VERSION 5.7 ;
  NOWIREEXTENSIONATPIN ON ;
  DIVIDERCHAR "/" ;
  BUSBITCHARS "[]" ;
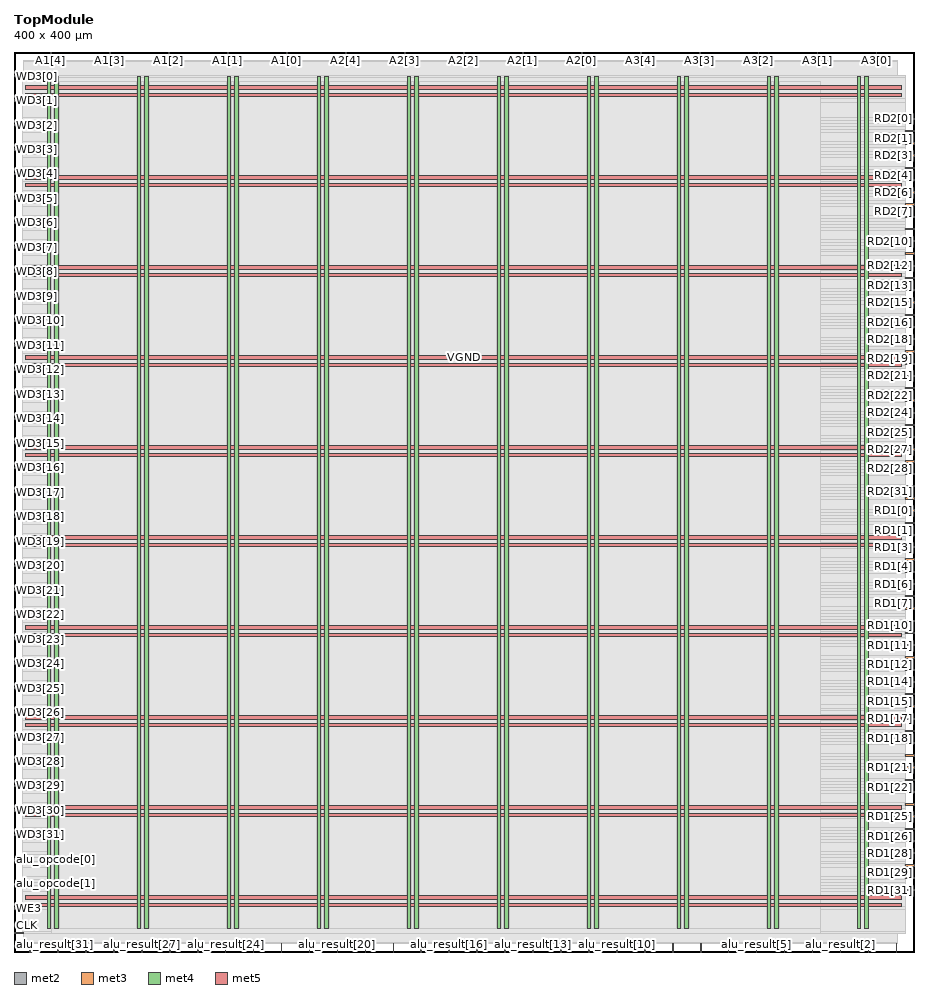
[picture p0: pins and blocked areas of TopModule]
MACRO TopModule
  CLASS BLOCK ;
  FOREIGN TopModule ;
  ORIGIN 0.000 0.000 ;
  SIZE 400.000 BY 400.000 ;
  PIN A1[0]
    DIRECTION INPUT ;
    USE SIGNAL ;
    ANTENNAGATEAREA 0.213000 ;
    PORT
      LAYER met2 ;
        RECT 121.070 396.000 121.350 400.000 ;
    END
  END A1[0]
  PIN A1[1]
    DIRECTION INPUT ;
    USE SIGNAL ;
    ANTENNAGATEAREA 0.159000 ;
    PORT
      LAYER met2 ;
        RECT 94.850 396.000 95.130 400.000 ;
    END
  END A1[1]
  PIN A1[2]
    DIRECTION INPUT ;
    USE SIGNAL ;
    ANTENNAGATEAREA 0.126000 ;
    PORT
      LAYER met2 ;
        RECT 68.630 396.000 68.910 400.000 ;
    END
  END A1[2]
  PIN A1[3]
    DIRECTION INPUT ;
    USE SIGNAL ;
    ANTENNAGATEAREA 0.159000 ;
    PORT
      LAYER met2 ;
        RECT 42.410 396.000 42.690 400.000 ;
    END
  END A1[3]
  PIN A1[4]
    DIRECTION INPUT ;
    USE SIGNAL ;
    ANTENNAGATEAREA 0.247500 ;
    PORT
      LAYER met2 ;
        RECT 16.190 396.000 16.470 400.000 ;
    END
  END A1[4]
  PIN A2[0]
    DIRECTION INPUT ;
    USE SIGNAL ;
    ANTENNAGATEAREA 0.990000 ;
    PORT
      LAYER met2 ;
        RECT 252.170 396.000 252.450 400.000 ;
    END
  END A2[0]
  PIN A2[1]
    DIRECTION INPUT ;
    USE SIGNAL ;
    ANTENNAGATEAREA 0.852000 ;
    PORT
      LAYER met2 ;
        RECT 225.950 396.000 226.230 400.000 ;
    END
  END A2[1]
  PIN A2[2]
    DIRECTION INPUT ;
    USE SIGNAL ;
    ANTENNAGATEAREA 0.159000 ;
    PORT
      LAYER met2 ;
        RECT 199.730 396.000 200.010 400.000 ;
    END
  END A2[2]
  PIN A2[3]
    DIRECTION INPUT ;
    USE SIGNAL ;
    ANTENNAGATEAREA 0.196500 ;
    PORT
      LAYER met2 ;
        RECT 173.510 396.000 173.790 400.000 ;
    END
  END A2[3]
  PIN A2[4]
    DIRECTION INPUT ;
    USE SIGNAL ;
    ANTENNAGATEAREA 0.213000 ;
    PORT
      LAYER met2 ;
        RECT 147.290 396.000 147.570 400.000 ;
    END
  END A2[4]
  PIN A3[0]
    DIRECTION INPUT ;
    USE SIGNAL ;
    ANTENNAGATEAREA 0.213000 ;
    PORT
      LAYER met2 ;
        RECT 383.270 396.000 383.550 400.000 ;
    END
  END A3[0]
  PIN A3[1]
    DIRECTION INPUT ;
    USE SIGNAL ;
    ANTENNAGATEAREA 0.247500 ;
    PORT
      LAYER met2 ;
        RECT 357.050 396.000 357.330 400.000 ;
    END
  END A3[1]
  PIN A3[2]
    DIRECTION INPUT ;
    USE SIGNAL ;
    ANTENNAGATEAREA 0.213000 ;
    PORT
      LAYER met2 ;
        RECT 330.830 396.000 331.110 400.000 ;
    END
  END A3[2]
  PIN A3[3]
    DIRECTION INPUT ;
    USE SIGNAL ;
    ANTENNAGATEAREA 0.213000 ;
    PORT
      LAYER met2 ;
        RECT 304.610 396.000 304.890 400.000 ;
    END
  END A3[3]
  PIN A3[4]
    DIRECTION INPUT ;
    USE SIGNAL ;
    ANTENNAGATEAREA 0.159000 ;
    PORT
      LAYER met2 ;
        RECT 278.390 396.000 278.670 400.000 ;
    END
  END A3[4]
  PIN CLK
    DIRECTION INPUT ;
    USE SIGNAL ;
    ANTENNAGATEAREA 0.852000 ;
    ANTENNADIFFAREA 0.434700 ;
    PORT
      LAYER met3 ;
        RECT 0.000 8.200 4.000 8.800 ;
    END
  END CLK
  PIN RD1[0]
    DIRECTION OUTPUT ;
    USE SIGNAL ;
    ANTENNADIFFAREA 0.340600 ;
    PORT
      LAYER met3 ;
        RECT 396.000 195.880 400.000 196.480 ;
    END
  END RD1[0]
  PIN RD1[10]
    DIRECTION OUTPUT ;
    USE SIGNAL ;
    ANTENNADIFFAREA 0.340600 ;
    PORT
      LAYER met3 ;
        RECT 396.000 141.480 400.000 142.080 ;
    END
  END RD1[10]
  PIN RD1[11]
    DIRECTION OUTPUT ;
    USE SIGNAL ;
    ANTENNADIFFAREA 0.340600 ;
    PORT
      LAYER met3 ;
        RECT 396.000 136.040 400.000 136.640 ;
    END
  END RD1[11]
  PIN RD1[12]
    DIRECTION OUTPUT ;
    USE SIGNAL ;
    ANTENNADIFFAREA 0.340600 ;
    PORT
      LAYER met3 ;
        RECT 396.000 130.600 400.000 131.200 ;
    END
  END RD1[12]
  PIN RD1[13]
    DIRECTION OUTPUT ;
    USE SIGNAL ;
    ANTENNADIFFAREA 0.340600 ;
    PORT
      LAYER met3 ;
        RECT 396.000 125.160 400.000 125.760 ;
    END
  END RD1[13]
  PIN RD1[14]
    DIRECTION OUTPUT ;
    USE SIGNAL ;
    ANTENNADIFFAREA 0.340600 ;
    PORT
      LAYER met3 ;
        RECT 396.000 119.720 400.000 120.320 ;
    END
  END RD1[14]
  PIN RD1[15]
    DIRECTION OUTPUT ;
    USE SIGNAL ;
    ANTENNADIFFAREA 0.340600 ;
    PORT
      LAYER met3 ;
        RECT 396.000 114.280 400.000 114.880 ;
    END
  END RD1[15]
  PIN RD1[16]
    DIRECTION OUTPUT ;
    USE SIGNAL ;
    ANTENNADIFFAREA 0.340600 ;
    PORT
      LAYER met3 ;
        RECT 396.000 108.840 400.000 109.440 ;
    END
  END RD1[16]
  PIN RD1[17]
    DIRECTION OUTPUT ;
    USE SIGNAL ;
    ANTENNADIFFAREA 0.340600 ;
    PORT
      LAYER met3 ;
        RECT 396.000 103.400 400.000 104.000 ;
    END
  END RD1[17]
  PIN RD1[18]
    DIRECTION OUTPUT ;
    USE SIGNAL ;
    ANTENNADIFFAREA 0.340600 ;
    PORT
      LAYER met3 ;
        RECT 396.000 97.960 400.000 98.560 ;
    END
  END RD1[18]
  PIN RD1[19]
    DIRECTION OUTPUT ;
    USE SIGNAL ;
    ANTENNADIFFAREA 0.340600 ;
    PORT
      LAYER met3 ;
        RECT 396.000 92.520 400.000 93.120 ;
    END
  END RD1[19]
  PIN RD1[1]
    DIRECTION OUTPUT ;
    USE SIGNAL ;
    ANTENNADIFFAREA 0.340600 ;
    PORT
      LAYER met3 ;
        RECT 396.000 190.440 400.000 191.040 ;
    END
  END RD1[1]
  PIN RD1[20]
    DIRECTION OUTPUT ;
    USE SIGNAL ;
    ANTENNADIFFAREA 0.340600 ;
    PORT
      LAYER met3 ;
        RECT 396.000 87.080 400.000 87.680 ;
    END
  END RD1[20]
  PIN RD1[21]
    DIRECTION OUTPUT ;
    USE SIGNAL ;
    ANTENNADIFFAREA 0.340600 ;
    PORT
      LAYER met3 ;
        RECT 396.000 81.640 400.000 82.240 ;
    END
  END RD1[21]
  PIN RD1[22]
    DIRECTION OUTPUT ;
    USE SIGNAL ;
    ANTENNADIFFAREA 0.340600 ;
    PORT
      LAYER met3 ;
        RECT 396.000 76.200 400.000 76.800 ;
    END
  END RD1[22]
  PIN RD1[23]
    DIRECTION OUTPUT ;
    USE SIGNAL ;
    ANTENNADIFFAREA 0.340600 ;
    PORT
      LAYER met3 ;
        RECT 396.000 70.760 400.000 71.360 ;
    END
  END RD1[23]
  PIN RD1[24]
    DIRECTION OUTPUT ;
    USE SIGNAL ;
    ANTENNADIFFAREA 0.340600 ;
    PORT
      LAYER met3 ;
        RECT 396.000 65.320 400.000 65.920 ;
    END
  END RD1[24]
  PIN RD1[25]
    DIRECTION OUTPUT ;
    USE SIGNAL ;
    ANTENNADIFFAREA 0.340600 ;
    PORT
      LAYER met3 ;
        RECT 396.000 59.880 400.000 60.480 ;
    END
  END RD1[25]
  PIN RD1[26]
    DIRECTION OUTPUT ;
    USE SIGNAL ;
    ANTENNADIFFAREA 0.340600 ;
    PORT
      LAYER met3 ;
        RECT 396.000 54.440 400.000 55.040 ;
    END
  END RD1[26]
  PIN RD1[27]
    DIRECTION OUTPUT ;
    USE SIGNAL ;
    ANTENNADIFFAREA 0.340600 ;
    PORT
      LAYER met3 ;
        RECT 396.000 49.000 400.000 49.600 ;
    END
  END RD1[27]
  PIN RD1[28]
    DIRECTION OUTPUT ;
    USE SIGNAL ;
    ANTENNADIFFAREA 0.340600 ;
    PORT
      LAYER met3 ;
        RECT 396.000 43.560 400.000 44.160 ;
    END
  END RD1[28]
  PIN RD1[29]
    DIRECTION OUTPUT ;
    USE SIGNAL ;
    ANTENNADIFFAREA 0.340600 ;
    PORT
      LAYER met3 ;
        RECT 396.000 38.120 400.000 38.720 ;
    END
  END RD1[29]
  PIN RD1[2]
    DIRECTION OUTPUT ;
    USE SIGNAL ;
    ANTENNADIFFAREA 0.340600 ;
    PORT
      LAYER met3 ;
        RECT 396.000 185.000 400.000 185.600 ;
    END
  END RD1[2]
  PIN RD1[30]
    DIRECTION OUTPUT ;
    USE SIGNAL ;
    ANTENNADIFFAREA 0.340600 ;
    PORT
      LAYER met3 ;
        RECT 396.000 32.680 400.000 33.280 ;
    END
  END RD1[30]
  PIN RD1[31]
    DIRECTION OUTPUT ;
    USE SIGNAL ;
    ANTENNADIFFAREA 0.340600 ;
    PORT
      LAYER met3 ;
        RECT 396.000 27.240 400.000 27.840 ;
    END
  END RD1[31]
  PIN RD1[3]
    DIRECTION OUTPUT ;
    USE SIGNAL ;
    ANTENNADIFFAREA 0.340600 ;
    PORT
      LAYER met3 ;
        RECT 396.000 179.560 400.000 180.160 ;
    END
  END RD1[3]
  PIN RD1[4]
    DIRECTION OUTPUT ;
    USE SIGNAL ;
    ANTENNADIFFAREA 0.340600 ;
    PORT
      LAYER met3 ;
        RECT 396.000 174.120 400.000 174.720 ;
    END
  END RD1[4]
  PIN RD1[5]
    DIRECTION OUTPUT ;
    USE SIGNAL ;
    ANTENNADIFFAREA 0.340600 ;
    PORT
      LAYER met3 ;
        RECT 396.000 168.680 400.000 169.280 ;
    END
  END RD1[5]
  PIN RD1[6]
    DIRECTION OUTPUT ;
    USE SIGNAL ;
    ANTENNADIFFAREA 0.340600 ;
    PORT
      LAYER met3 ;
        RECT 396.000 163.240 400.000 163.840 ;
    END
  END RD1[6]
  PIN RD1[7]
    DIRECTION OUTPUT ;
    USE SIGNAL ;
    ANTENNADIFFAREA 0.340600 ;
    PORT
      LAYER met3 ;
        RECT 396.000 157.800 400.000 158.400 ;
    END
  END RD1[7]
  PIN RD1[8]
    DIRECTION OUTPUT ;
    USE SIGNAL ;
    ANTENNADIFFAREA 0.340600 ;
    PORT
      LAYER met3 ;
        RECT 396.000 152.360 400.000 152.960 ;
    END
  END RD1[8]
  PIN RD1[9]
    DIRECTION OUTPUT ;
    USE SIGNAL ;
    ANTENNADIFFAREA 0.340600 ;
    PORT
      LAYER met3 ;
        RECT 396.000 146.920 400.000 147.520 ;
    END
  END RD1[9]
  PIN RD2[0]
    DIRECTION OUTPUT ;
    USE SIGNAL ;
    ANTENNADIFFAREA 0.340600 ;
    PORT
      LAYER met3 ;
        RECT 396.000 369.960 400.000 370.560 ;
    END
  END RD2[0]
  PIN RD2[10]
    DIRECTION OUTPUT ;
    USE SIGNAL ;
    ANTENNADIFFAREA 0.340600 ;
    PORT
      LAYER met3 ;
        RECT 396.000 315.560 400.000 316.160 ;
    END
  END RD2[10]
  PIN RD2[11]
    DIRECTION OUTPUT ;
    USE SIGNAL ;
    ANTENNADIFFAREA 0.340600 ;
    PORT
      LAYER met3 ;
        RECT 396.000 310.120 400.000 310.720 ;
    END
  END RD2[11]
  PIN RD2[12]
    DIRECTION OUTPUT ;
    USE SIGNAL ;
    ANTENNADIFFAREA 0.340600 ;
    PORT
      LAYER met3 ;
        RECT 396.000 304.680 400.000 305.280 ;
    END
  END RD2[12]
  PIN RD2[13]
    DIRECTION OUTPUT ;
    USE SIGNAL ;
    ANTENNADIFFAREA 0.340600 ;
    PORT
      LAYER met3 ;
        RECT 396.000 299.240 400.000 299.840 ;
    END
  END RD2[13]
  PIN RD2[14]
    DIRECTION OUTPUT ;
    USE SIGNAL ;
    ANTENNADIFFAREA 0.340600 ;
    PORT
      LAYER met3 ;
        RECT 396.000 293.800 400.000 294.400 ;
    END
  END RD2[14]
  PIN RD2[15]
    DIRECTION OUTPUT ;
    USE SIGNAL ;
    ANTENNADIFFAREA 0.340600 ;
    PORT
      LAYER met3 ;
        RECT 396.000 288.360 400.000 288.960 ;
    END
  END RD2[15]
  PIN RD2[16]
    DIRECTION OUTPUT ;
    USE SIGNAL ;
    ANTENNADIFFAREA 0.340600 ;
    PORT
      LAYER met3 ;
        RECT 396.000 282.920 400.000 283.520 ;
    END
  END RD2[16]
  PIN RD2[17]
    DIRECTION OUTPUT ;
    USE SIGNAL ;
    ANTENNADIFFAREA 0.340600 ;
    PORT
      LAYER met3 ;
        RECT 396.000 277.480 400.000 278.080 ;
    END
  END RD2[17]
  PIN RD2[18]
    DIRECTION OUTPUT ;
    USE SIGNAL ;
    ANTENNADIFFAREA 0.340600 ;
    PORT
      LAYER met3 ;
        RECT 396.000 272.040 400.000 272.640 ;
    END
  END RD2[18]
  PIN RD2[19]
    DIRECTION OUTPUT ;
    USE SIGNAL ;
    ANTENNADIFFAREA 0.340600 ;
    PORT
      LAYER met3 ;
        RECT 396.000 266.600 400.000 267.200 ;
    END
  END RD2[19]
  PIN RD2[1]
    DIRECTION OUTPUT ;
    USE SIGNAL ;
    ANTENNADIFFAREA 0.340600 ;
    PORT
      LAYER met3 ;
        RECT 396.000 364.520 400.000 365.120 ;
    END
  END RD2[1]
  PIN RD2[20]
    DIRECTION OUTPUT ;
    USE SIGNAL ;
    ANTENNADIFFAREA 0.340600 ;
    PORT
      LAYER met3 ;
        RECT 396.000 261.160 400.000 261.760 ;
    END
  END RD2[20]
  PIN RD2[21]
    DIRECTION OUTPUT ;
    USE SIGNAL ;
    ANTENNADIFFAREA 0.340600 ;
    PORT
      LAYER met3 ;
        RECT 396.000 255.720 400.000 256.320 ;
    END
  END RD2[21]
  PIN RD2[22]
    DIRECTION OUTPUT ;
    USE SIGNAL ;
    ANTENNADIFFAREA 0.340600 ;
    PORT
      LAYER met3 ;
        RECT 396.000 250.280 400.000 250.880 ;
    END
  END RD2[22]
  PIN RD2[23]
    DIRECTION OUTPUT ;
    USE SIGNAL ;
    ANTENNADIFFAREA 0.340600 ;
    PORT
      LAYER met3 ;
        RECT 396.000 244.840 400.000 245.440 ;
    END
  END RD2[23]
  PIN RD2[24]
    DIRECTION OUTPUT ;
    USE SIGNAL ;
    ANTENNADIFFAREA 0.340600 ;
    PORT
      LAYER met3 ;
        RECT 396.000 239.400 400.000 240.000 ;
    END
  END RD2[24]
  PIN RD2[25]
    DIRECTION OUTPUT ;
    USE SIGNAL ;
    ANTENNADIFFAREA 0.340600 ;
    PORT
      LAYER met3 ;
        RECT 396.000 233.960 400.000 234.560 ;
    END
  END RD2[25]
  PIN RD2[26]
    DIRECTION OUTPUT ;
    USE SIGNAL ;
    ANTENNADIFFAREA 0.340600 ;
    PORT
      LAYER met3 ;
        RECT 396.000 228.520 400.000 229.120 ;
    END
  END RD2[26]
  PIN RD2[27]
    DIRECTION OUTPUT ;
    USE SIGNAL ;
    ANTENNADIFFAREA 0.340600 ;
    PORT
      LAYER met3 ;
        RECT 396.000 223.080 400.000 223.680 ;
    END
  END RD2[27]
  PIN RD2[28]
    DIRECTION OUTPUT ;
    USE SIGNAL ;
    ANTENNADIFFAREA 0.340600 ;
    PORT
      LAYER met3 ;
        RECT 396.000 217.640 400.000 218.240 ;
    END
  END RD2[28]
  PIN RD2[29]
    DIRECTION OUTPUT ;
    USE SIGNAL ;
    ANTENNADIFFAREA 0.340600 ;
    PORT
      LAYER met3 ;
        RECT 396.000 212.200 400.000 212.800 ;
    END
  END RD2[29]
  PIN RD2[2]
    DIRECTION OUTPUT ;
    USE SIGNAL ;
    ANTENNADIFFAREA 0.340600 ;
    PORT
      LAYER met3 ;
        RECT 396.000 359.080 400.000 359.680 ;
    END
  END RD2[2]
  PIN RD2[30]
    DIRECTION OUTPUT ;
    USE SIGNAL ;
    ANTENNADIFFAREA 0.340600 ;
    PORT
      LAYER met3 ;
        RECT 396.000 206.760 400.000 207.360 ;
    END
  END RD2[30]
  PIN RD2[31]
    DIRECTION OUTPUT ;
    USE SIGNAL ;
    ANTENNADIFFAREA 0.340600 ;
    PORT
      LAYER met3 ;
        RECT 396.000 201.320 400.000 201.920 ;
    END
  END RD2[31]
  PIN RD2[3]
    DIRECTION OUTPUT ;
    USE SIGNAL ;
    ANTENNADIFFAREA 0.340600 ;
    PORT
      LAYER met3 ;
        RECT 396.000 353.640 400.000 354.240 ;
    END
  END RD2[3]
  PIN RD2[4]
    DIRECTION OUTPUT ;
    USE SIGNAL ;
    ANTENNADIFFAREA 0.340600 ;
    PORT
      LAYER met3 ;
        RECT 396.000 348.200 400.000 348.800 ;
    END
  END RD2[4]
  PIN RD2[5]
    DIRECTION OUTPUT ;
    USE SIGNAL ;
    ANTENNADIFFAREA 0.340600 ;
    PORT
      LAYER met3 ;
        RECT 396.000 342.760 400.000 343.360 ;
    END
  END RD2[5]
  PIN RD2[6]
    DIRECTION OUTPUT ;
    USE SIGNAL ;
    ANTENNADIFFAREA 0.340600 ;
    PORT
      LAYER met3 ;
        RECT 396.000 337.320 400.000 337.920 ;
    END
  END RD2[6]
  PIN RD2[7]
    DIRECTION OUTPUT ;
    USE SIGNAL ;
    ANTENNADIFFAREA 0.340600 ;
    PORT
      LAYER met3 ;
        RECT 396.000 331.880 400.000 332.480 ;
    END
  END RD2[7]
  PIN RD2[8]
    DIRECTION OUTPUT ;
    USE SIGNAL ;
    ANTENNADIFFAREA 0.340600 ;
    PORT
      LAYER met3 ;
        RECT 396.000 326.440 400.000 327.040 ;
    END
  END RD2[8]
  PIN RD2[9]
    DIRECTION OUTPUT ;
    USE SIGNAL ;
    ANTENNADIFFAREA 0.340600 ;
    PORT
      LAYER met3 ;
        RECT 396.000 321.000 400.000 321.600 ;
    END
  END RD2[9]
  PIN VGND
    DIRECTION INOUT ;
    USE GROUND ;
    PORT
      LAYER met4 ;
        RECT 18.020 10.640 19.620 389.200 ;
    END
    PORT
      LAYER met4 ;
        RECT 58.020 10.640 59.620 389.200 ;
    END
    PORT
      LAYER met4 ;
        RECT 98.020 10.640 99.620 389.200 ;
    END
    PORT
      LAYER met4 ;
        RECT 138.020 10.640 139.620 389.200 ;
    END
    PORT
      LAYER met4 ;
        RECT 178.020 10.640 179.620 389.200 ;
    END
    PORT
      LAYER met4 ;
        RECT 218.020 10.640 219.620 389.200 ;
    END
    PORT
      LAYER met4 ;
        RECT 258.020 10.640 259.620 389.200 ;
    END
    PORT
      LAYER met4 ;
        RECT 298.020 10.640 299.620 389.200 ;
    END
    PORT
      LAYER met4 ;
        RECT 338.020 10.640 339.620 389.200 ;
    END
    PORT
      LAYER met4 ;
        RECT 378.020 10.640 379.620 389.200 ;
    END
    PORT
      LAYER met5 ;
        RECT 5.280 23.380 394.460 24.980 ;
    END
    PORT
      LAYER met5 ;
        RECT 5.280 63.380 394.460 64.980 ;
    END
    PORT
      LAYER met5 ;
        RECT 5.280 103.380 394.460 104.980 ;
    END
    PORT
      LAYER met5 ;
        RECT 5.280 143.380 394.460 144.980 ;
    END
    PORT
      LAYER met5 ;
        RECT 5.280 183.380 394.460 184.980 ;
    END
    PORT
      LAYER met5 ;
        RECT 5.280 223.380 394.460 224.980 ;
    END
    PORT
      LAYER met5 ;
        RECT 5.280 263.380 394.460 264.980 ;
    END
    PORT
      LAYER met5 ;
        RECT 5.280 303.380 394.460 304.980 ;
    END
    PORT
      LAYER met5 ;
        RECT 5.280 343.380 394.460 344.980 ;
    END
    PORT
      LAYER met5 ;
        RECT 5.280 383.380 394.460 384.980 ;
    END
  END VGND
  PIN VPWR
    DIRECTION INOUT ;
    USE POWER ;
    PORT
      LAYER met4 ;
        RECT 14.720 10.640 16.320 389.200 ;
    END
    PORT
      LAYER met4 ;
        RECT 54.720 10.640 56.320 389.200 ;
    END
    PORT
      LAYER met4 ;
        RECT 94.720 10.640 96.320 389.200 ;
    END
    PORT
      LAYER met4 ;
        RECT 134.720 10.640 136.320 389.200 ;
    END
    PORT
      LAYER met4 ;
        RECT 174.720 10.640 176.320 389.200 ;
    END
    PORT
      LAYER met4 ;
        RECT 214.720 10.640 216.320 389.200 ;
    END
    PORT
      LAYER met4 ;
        RECT 254.720 10.640 256.320 389.200 ;
    END
    PORT
      LAYER met4 ;
        RECT 294.720 10.640 296.320 389.200 ;
    END
    PORT
      LAYER met4 ;
        RECT 334.720 10.640 336.320 389.200 ;
    END
    PORT
      LAYER met4 ;
        RECT 374.720 10.640 376.320 389.200 ;
    END
    PORT
      LAYER met5 ;
        RECT 5.280 20.080 394.460 21.680 ;
    END
    PORT
      LAYER met5 ;
        RECT 5.280 60.080 394.460 61.680 ;
    END
    PORT
      LAYER met5 ;
        RECT 5.280 100.080 394.460 101.680 ;
    END
    PORT
      LAYER met5 ;
        RECT 5.280 140.080 394.460 141.680 ;
    END
    PORT
      LAYER met5 ;
        RECT 5.280 180.080 394.460 181.680 ;
    END
    PORT
      LAYER met5 ;
        RECT 5.280 220.080 394.460 221.680 ;
    END
    PORT
      LAYER met5 ;
        RECT 5.280 260.080 394.460 261.680 ;
    END
    PORT
      LAYER met5 ;
        RECT 5.280 300.080 394.460 301.680 ;
    END
    PORT
      LAYER met5 ;
        RECT 5.280 340.080 394.460 341.680 ;
    END
    PORT
      LAYER met5 ;
        RECT 5.280 380.080 394.460 381.680 ;
    END
  END VPWR
  PIN WD3[0]
    DIRECTION INPUT ;
    USE SIGNAL ;
    ANTENNAGATEAREA 0.159000 ;
    PORT
      LAYER met3 ;
        RECT 0.000 389.000 4.000 389.600 ;
    END
  END WD3[0]
  PIN WD3[10]
    DIRECTION INPUT ;
    USE SIGNAL ;
    ANTENNAGATEAREA 0.159000 ;
    PORT
      LAYER met3 ;
        RECT 0.000 280.200 4.000 280.800 ;
    END
  END WD3[10]
  PIN WD3[11]
    DIRECTION INPUT ;
    USE SIGNAL ;
    ANTENNAGATEAREA 0.213000 ;
    PORT
      LAYER met3 ;
        RECT 0.000 269.320 4.000 269.920 ;
    END
  END WD3[11]
  PIN WD3[12]
    DIRECTION INPUT ;
    USE SIGNAL ;
    ANTENNAGATEAREA 0.213000 ;
    PORT
      LAYER met3 ;
        RECT 0.000 258.440 4.000 259.040 ;
    END
  END WD3[12]
  PIN WD3[13]
    DIRECTION INPUT ;
    USE SIGNAL ;
    ANTENNAGATEAREA 0.159000 ;
    PORT
      LAYER met3 ;
        RECT 0.000 247.560 4.000 248.160 ;
    END
  END WD3[13]
  PIN WD3[14]
    DIRECTION INPUT ;
    USE SIGNAL ;
    ANTENNAGATEAREA 0.213000 ;
    PORT
      LAYER met3 ;
        RECT 0.000 236.680 4.000 237.280 ;
    END
  END WD3[14]
  PIN WD3[15]
    DIRECTION INPUT ;
    USE SIGNAL ;
    ANTENNAGATEAREA 0.213000 ;
    PORT
      LAYER met3 ;
        RECT 0.000 225.800 4.000 226.400 ;
    END
  END WD3[15]
  PIN WD3[16]
    DIRECTION INPUT ;
    USE SIGNAL ;
    ANTENNAGATEAREA 0.196500 ;
    PORT
      LAYER met3 ;
        RECT 0.000 214.920 4.000 215.520 ;
    END
  END WD3[16]
  PIN WD3[17]
    DIRECTION INPUT ;
    USE SIGNAL ;
    ANTENNAGATEAREA 0.213000 ;
    PORT
      LAYER met3 ;
        RECT 0.000 204.040 4.000 204.640 ;
    END
  END WD3[17]
  PIN WD3[18]
    DIRECTION INPUT ;
    USE SIGNAL ;
    ANTENNAGATEAREA 0.196500 ;
    PORT
      LAYER met3 ;
        RECT 0.000 193.160 4.000 193.760 ;
    END
  END WD3[18]
  PIN WD3[19]
    DIRECTION INPUT ;
    USE SIGNAL ;
    ANTENNAGATEAREA 0.126000 ;
    PORT
      LAYER met3 ;
        RECT 0.000 182.280 4.000 182.880 ;
    END
  END WD3[19]
  PIN WD3[1]
    DIRECTION INPUT ;
    USE SIGNAL ;
    ANTENNAGATEAREA 0.159000 ;
    PORT
      LAYER met3 ;
        RECT 0.000 378.120 4.000 378.720 ;
    END
  END WD3[1]
  PIN WD3[20]
    DIRECTION INPUT ;
    USE SIGNAL ;
    ANTENNAGATEAREA 0.213000 ;
    PORT
      LAYER met3 ;
        RECT 0.000 171.400 4.000 172.000 ;
    END
  END WD3[20]
  PIN WD3[21]
    DIRECTION INPUT ;
    USE SIGNAL ;
    ANTENNAGATEAREA 0.159000 ;
    PORT
      LAYER met3 ;
        RECT 0.000 160.520 4.000 161.120 ;
    END
  END WD3[21]
  PIN WD3[22]
    DIRECTION INPUT ;
    USE SIGNAL ;
    ANTENNAGATEAREA 0.126000 ;
    PORT
      LAYER met3 ;
        RECT 0.000 149.640 4.000 150.240 ;
    END
  END WD3[22]
  PIN WD3[23]
    DIRECTION INPUT ;
    USE SIGNAL ;
    ANTENNAGATEAREA 0.196500 ;
    PORT
      LAYER met3 ;
        RECT 0.000 138.760 4.000 139.360 ;
    END
  END WD3[23]
  PIN WD3[24]
    DIRECTION INPUT ;
    USE SIGNAL ;
    ANTENNAGATEAREA 0.213000 ;
    PORT
      LAYER met3 ;
        RECT 0.000 127.880 4.000 128.480 ;
    END
  END WD3[24]
  PIN WD3[25]
    DIRECTION INPUT ;
    USE SIGNAL ;
    ANTENNAGATEAREA 0.213000 ;
    PORT
      LAYER met3 ;
        RECT 0.000 117.000 4.000 117.600 ;
    END
  END WD3[25]
  PIN WD3[26]
    DIRECTION INPUT ;
    USE SIGNAL ;
    ANTENNAGATEAREA 0.159000 ;
    PORT
      LAYER met3 ;
        RECT 0.000 106.120 4.000 106.720 ;
    END
  END WD3[26]
  PIN WD3[27]
    DIRECTION INPUT ;
    USE SIGNAL ;
    ANTENNAGATEAREA 0.213000 ;
    PORT
      LAYER met3 ;
        RECT 0.000 95.240 4.000 95.840 ;
    END
  END WD3[27]
  PIN WD3[28]
    DIRECTION INPUT ;
    USE SIGNAL ;
    ANTENNAGATEAREA 0.196500 ;
    PORT
      LAYER met3 ;
        RECT 0.000 84.360 4.000 84.960 ;
    END
  END WD3[28]
  PIN WD3[29]
    DIRECTION INPUT ;
    USE SIGNAL ;
    ANTENNAGATEAREA 0.196500 ;
    PORT
      LAYER met3 ;
        RECT 0.000 73.480 4.000 74.080 ;
    END
  END WD3[29]
  PIN WD3[2]
    DIRECTION INPUT ;
    USE SIGNAL ;
    ANTENNAGATEAREA 0.159000 ;
    PORT
      LAYER met3 ;
        RECT 0.000 367.240 4.000 367.840 ;
    END
  END WD3[2]
  PIN WD3[30]
    DIRECTION INPUT ;
    USE SIGNAL ;
    ANTENNAGATEAREA 0.213000 ;
    PORT
      LAYER met3 ;
        RECT 0.000 62.600 4.000 63.200 ;
    END
  END WD3[30]
  PIN WD3[31]
    DIRECTION INPUT ;
    USE SIGNAL ;
    ANTENNAGATEAREA 0.213000 ;
    PORT
      LAYER met3 ;
        RECT 0.000 51.720 4.000 52.320 ;
    END
  END WD3[31]
  PIN WD3[3]
    DIRECTION INPUT ;
    USE SIGNAL ;
    ANTENNAGATEAREA 0.159000 ;
    PORT
      LAYER met3 ;
        RECT 0.000 356.360 4.000 356.960 ;
    END
  END WD3[3]
  PIN WD3[4]
    DIRECTION INPUT ;
    USE SIGNAL ;
    ANTENNAGATEAREA 0.213000 ;
    PORT
      LAYER met3 ;
        RECT 0.000 345.480 4.000 346.080 ;
    END
  END WD3[4]
  PIN WD3[5]
    DIRECTION INPUT ;
    USE SIGNAL ;
    ANTENNAGATEAREA 0.159000 ;
    PORT
      LAYER met3 ;
        RECT 0.000 334.600 4.000 335.200 ;
    END
  END WD3[5]
  PIN WD3[6]
    DIRECTION INPUT ;
    USE SIGNAL ;
    ANTENNAGATEAREA 0.213000 ;
    PORT
      LAYER met3 ;
        RECT 0.000 323.720 4.000 324.320 ;
    END
  END WD3[6]
  PIN WD3[7]
    DIRECTION INPUT ;
    USE SIGNAL ;
    ANTENNAGATEAREA 0.213000 ;
    PORT
      LAYER met3 ;
        RECT 0.000 312.840 4.000 313.440 ;
    END
  END WD3[7]
  PIN WD3[8]
    DIRECTION INPUT ;
    USE SIGNAL ;
    ANTENNAGATEAREA 0.159000 ;
    PORT
      LAYER met3 ;
        RECT 0.000 301.960 4.000 302.560 ;
    END
  END WD3[8]
  PIN WD3[9]
    DIRECTION INPUT ;
    USE SIGNAL ;
    ANTENNAGATEAREA 0.159000 ;
    PORT
      LAYER met3 ;
        RECT 0.000 291.080 4.000 291.680 ;
    END
  END WD3[9]
  PIN WE3
    DIRECTION INPUT ;
    USE SIGNAL ;
    ANTENNAGATEAREA 0.247500 ;
    PORT
      LAYER met3 ;
        RECT 0.000 19.080 4.000 19.680 ;
    END
  END WE3
  PIN alu_opcode[0]
    DIRECTION INPUT ;
    USE SIGNAL ;
    ANTENNAGATEAREA 0.213000 ;
    PORT
      LAYER met3 ;
        RECT 0.000 40.840 4.000 41.440 ;
    END
  END alu_opcode[0]
  PIN alu_opcode[1]
    DIRECTION INPUT ;
    USE SIGNAL ;
    ANTENNAGATEAREA 0.159000 ;
    PORT
      LAYER met3 ;
        RECT 0.000 29.960 4.000 30.560 ;
    END
  END alu_opcode[1]
  PIN alu_result[0]
    DIRECTION OUTPUT ;
    USE SIGNAL ;
    ANTENNADIFFAREA 0.340600 ;
    PORT
      LAYER met2 ;
        RECT 392.010 0.000 392.290 4.000 ;
    END
  END alu_result[0]
  PIN alu_result[10]
    DIRECTION OUTPUT ;
    USE SIGNAL ;
    ANTENNADIFFAREA 0.340600 ;
    PORT
      LAYER met2 ;
        RECT 267.810 0.000 268.090 4.000 ;
    END
  END alu_result[10]
  PIN alu_result[11]
    DIRECTION OUTPUT ;
    USE SIGNAL ;
    ANTENNADIFFAREA 0.340600 ;
    PORT
      LAYER met2 ;
        RECT 255.390 0.000 255.670 4.000 ;
    END
  END alu_result[11]
  PIN alu_result[12]
    DIRECTION OUTPUT ;
    USE SIGNAL ;
    ANTENNADIFFAREA 0.340600 ;
    PORT
      LAYER met2 ;
        RECT 242.970 0.000 243.250 4.000 ;
    END
  END alu_result[12]
  PIN alu_result[13]
    DIRECTION OUTPUT ;
    USE SIGNAL ;
    ANTENNADIFFAREA 0.340600 ;
    PORT
      LAYER met2 ;
        RECT 230.550 0.000 230.830 4.000 ;
    END
  END alu_result[13]
  PIN alu_result[14]
    DIRECTION OUTPUT ;
    USE SIGNAL ;
    ANTENNADIFFAREA 0.340600 ;
    PORT
      LAYER met2 ;
        RECT 218.130 0.000 218.410 4.000 ;
    END
  END alu_result[14]
  PIN alu_result[15]
    DIRECTION OUTPUT ;
    USE SIGNAL ;
    ANTENNADIFFAREA 0.340600 ;
    PORT
      LAYER met2 ;
        RECT 205.710 0.000 205.990 4.000 ;
    END
  END alu_result[15]
  PIN alu_result[16]
    DIRECTION OUTPUT ;
    USE SIGNAL ;
    ANTENNADIFFAREA 0.340600 ;
    PORT
      LAYER met2 ;
        RECT 193.290 0.000 193.570 4.000 ;
    END
  END alu_result[16]
  PIN alu_result[17]
    DIRECTION OUTPUT ;
    USE SIGNAL ;
    ANTENNADIFFAREA 0.340600 ;
    PORT
      LAYER met2 ;
        RECT 180.870 0.000 181.150 4.000 ;
    END
  END alu_result[17]
  PIN alu_result[18]
    DIRECTION OUTPUT ;
    USE SIGNAL ;
    ANTENNADIFFAREA 0.340600 ;
    PORT
      LAYER met2 ;
        RECT 168.450 0.000 168.730 4.000 ;
    END
  END alu_result[18]
  PIN alu_result[19]
    DIRECTION OUTPUT ;
    USE SIGNAL ;
    ANTENNADIFFAREA 0.340600 ;
    PORT
      LAYER met2 ;
        RECT 156.030 0.000 156.310 4.000 ;
    END
  END alu_result[19]
  PIN alu_result[1]
    DIRECTION OUTPUT ;
    USE SIGNAL ;
    ANTENNADIFFAREA 0.340600 ;
    PORT
      LAYER met2 ;
        RECT 379.590 0.000 379.870 4.000 ;
    END
  END alu_result[1]
  PIN alu_result[20]
    DIRECTION OUTPUT ;
    USE SIGNAL ;
    ANTENNADIFFAREA 0.340600 ;
    PORT
      LAYER met2 ;
        RECT 143.610 0.000 143.890 4.000 ;
    END
  END alu_result[20]
  PIN alu_result[21]
    DIRECTION OUTPUT ;
    USE SIGNAL ;
    ANTENNADIFFAREA 0.340600 ;
    PORT
      LAYER met2 ;
        RECT 131.190 0.000 131.470 4.000 ;
    END
  END alu_result[21]
  PIN alu_result[22]
    DIRECTION OUTPUT ;
    USE SIGNAL ;
    ANTENNADIFFAREA 0.340600 ;
    PORT
      LAYER met2 ;
        RECT 118.770 0.000 119.050 4.000 ;
    END
  END alu_result[22]
  PIN alu_result[23]
    DIRECTION OUTPUT ;
    USE SIGNAL ;
    ANTENNADIFFAREA 0.340600 ;
    PORT
      LAYER met2 ;
        RECT 106.350 0.000 106.630 4.000 ;
    END
  END alu_result[23]
  PIN alu_result[24]
    DIRECTION OUTPUT ;
    USE SIGNAL ;
    ANTENNADIFFAREA 0.340600 ;
    PORT
      LAYER met2 ;
        RECT 93.930 0.000 94.210 4.000 ;
    END
  END alu_result[24]
  PIN alu_result[25]
    DIRECTION OUTPUT ;
    USE SIGNAL ;
    ANTENNADIFFAREA 0.340600 ;
    PORT
      LAYER met2 ;
        RECT 81.510 0.000 81.790 4.000 ;
    END
  END alu_result[25]
  PIN alu_result[26]
    DIRECTION OUTPUT ;
    USE SIGNAL ;
    ANTENNADIFFAREA 0.340600 ;
    PORT
      LAYER met2 ;
        RECT 69.090 0.000 69.370 4.000 ;
    END
  END alu_result[26]
  PIN alu_result[27]
    DIRECTION OUTPUT ;
    USE SIGNAL ;
    ANTENNADIFFAREA 0.340600 ;
    PORT
      LAYER met2 ;
        RECT 56.670 0.000 56.950 4.000 ;
    END
  END alu_result[27]
  PIN alu_result[28]
    DIRECTION OUTPUT ;
    USE SIGNAL ;
    ANTENNADIFFAREA 0.340600 ;
    PORT
      LAYER met2 ;
        RECT 44.250 0.000 44.530 4.000 ;
    END
  END alu_result[28]
  PIN alu_result[29]
    DIRECTION OUTPUT ;
    USE SIGNAL ;
    ANTENNADIFFAREA 0.340600 ;
    PORT
      LAYER met2 ;
        RECT 31.830 0.000 32.110 4.000 ;
    END
  END alu_result[29]
  PIN alu_result[2]
    DIRECTION OUTPUT ;
    USE SIGNAL ;
    ANTENNADIFFAREA 0.340600 ;
    PORT
      LAYER met2 ;
        RECT 367.170 0.000 367.450 4.000 ;
    END
  END alu_result[2]
  PIN alu_result[30]
    DIRECTION OUTPUT ;
    USE SIGNAL ;
    ANTENNADIFFAREA 0.340600 ;
    PORT
      LAYER met2 ;
        RECT 19.410 0.000 19.690 4.000 ;
    END
  END alu_result[30]
  PIN alu_result[31]
    DIRECTION OUTPUT ;
    USE SIGNAL ;
    ANTENNADIFFAREA 0.340600 ;
    PORT
      LAYER met2 ;
        RECT 6.990 0.000 7.270 4.000 ;
    END
  END alu_result[31]
  PIN alu_result[3]
    DIRECTION OUTPUT ;
    USE SIGNAL ;
    ANTENNADIFFAREA 0.340600 ;
    PORT
      LAYER met2 ;
        RECT 354.750 0.000 355.030 4.000 ;
    END
  END alu_result[3]
  PIN alu_result[4]
    DIRECTION OUTPUT ;
    USE SIGNAL ;
    ANTENNADIFFAREA 0.340600 ;
    PORT
      LAYER met2 ;
        RECT 342.330 0.000 342.610 4.000 ;
    END
  END alu_result[4]
  PIN alu_result[5]
    DIRECTION OUTPUT ;
    USE SIGNAL ;
    ANTENNADIFFAREA 0.340600 ;
    PORT
      LAYER met2 ;
        RECT 329.910 0.000 330.190 4.000 ;
    END
  END alu_result[5]
  PIN alu_result[6]
    DIRECTION OUTPUT ;
    USE SIGNAL ;
    ANTENNADIFFAREA 0.340600 ;
    PORT
      LAYER met2 ;
        RECT 317.490 0.000 317.770 4.000 ;
    END
  END alu_result[6]
  PIN alu_result[7]
    DIRECTION OUTPUT ;
    USE SIGNAL ;
    ANTENNADIFFAREA 0.340600 ;
    PORT
      LAYER met2 ;
        RECT 305.070 0.000 305.350 4.000 ;
    END
  END alu_result[7]
  PIN alu_result[8]
    DIRECTION OUTPUT ;
    USE SIGNAL ;
    ANTENNADIFFAREA 0.340600 ;
    PORT
      LAYER met2 ;
        RECT 292.650 0.000 292.930 4.000 ;
    END
  END alu_result[8]
  PIN alu_result[9]
    DIRECTION OUTPUT ;
    USE SIGNAL ;
    ANTENNADIFFAREA 0.340600 ;
    PORT
      LAYER met2 ;
        RECT 280.230 0.000 280.510 4.000 ;
    END
  END alu_result[9]
  OBS
      LAYER nwell ;
        RECT 5.330 10.795 394.410 389.150 ;
      LAYER li1 ;
        RECT 5.520 10.795 394.220 389.045 ;
      LAYER met1 ;
        RECT 4.210 10.640 394.220 389.200 ;
      LAYER met2 ;
        RECT 4.230 395.720 15.910 396.170 ;
        RECT 16.750 395.720 42.130 396.170 ;
        RECT 42.970 395.720 68.350 396.170 ;
        RECT 69.190 395.720 94.570 396.170 ;
        RECT 95.410 395.720 120.790 396.170 ;
        RECT 121.630 395.720 147.010 396.170 ;
        RECT 147.850 395.720 173.230 396.170 ;
        RECT 174.070 395.720 199.450 396.170 ;
        RECT 200.290 395.720 225.670 396.170 ;
        RECT 226.510 395.720 251.890 396.170 ;
        RECT 252.730 395.720 278.110 396.170 ;
        RECT 278.950 395.720 304.330 396.170 ;
        RECT 305.170 395.720 330.550 396.170 ;
        RECT 331.390 395.720 356.770 396.170 ;
        RECT 357.610 395.720 382.990 396.170 ;
        RECT 383.830 395.720 392.750 396.170 ;
        RECT 4.230 4.280 392.750 395.720 ;
        RECT 4.230 4.000 6.710 4.280 ;
        RECT 7.550 4.000 19.130 4.280 ;
        RECT 19.970 4.000 31.550 4.280 ;
        RECT 32.390 4.000 43.970 4.280 ;
        RECT 44.810 4.000 56.390 4.280 ;
        RECT 57.230 4.000 68.810 4.280 ;
        RECT 69.650 4.000 81.230 4.280 ;
        RECT 82.070 4.000 93.650 4.280 ;
        RECT 94.490 4.000 106.070 4.280 ;
        RECT 106.910 4.000 118.490 4.280 ;
        RECT 119.330 4.000 130.910 4.280 ;
        RECT 131.750 4.000 143.330 4.280 ;
        RECT 144.170 4.000 155.750 4.280 ;
        RECT 156.590 4.000 168.170 4.280 ;
        RECT 169.010 4.000 180.590 4.280 ;
        RECT 181.430 4.000 193.010 4.280 ;
        RECT 193.850 4.000 205.430 4.280 ;
        RECT 206.270 4.000 217.850 4.280 ;
        RECT 218.690 4.000 230.270 4.280 ;
        RECT 231.110 4.000 242.690 4.280 ;
        RECT 243.530 4.000 255.110 4.280 ;
        RECT 255.950 4.000 267.530 4.280 ;
        RECT 268.370 4.000 279.950 4.280 ;
        RECT 280.790 4.000 292.370 4.280 ;
        RECT 293.210 4.000 304.790 4.280 ;
        RECT 305.630 4.000 317.210 4.280 ;
        RECT 318.050 4.000 329.630 4.280 ;
        RECT 330.470 4.000 342.050 4.280 ;
        RECT 342.890 4.000 354.470 4.280 ;
        RECT 355.310 4.000 366.890 4.280 ;
        RECT 367.730 4.000 379.310 4.280 ;
        RECT 380.150 4.000 391.730 4.280 ;
        RECT 392.570 4.000 392.750 4.280 ;
      LAYER met3 ;
        RECT 4.400 388.600 396.000 389.450 ;
        RECT 3.990 379.120 396.000 388.600 ;
        RECT 4.400 377.720 396.000 379.120 ;
        RECT 3.990 370.960 396.000 377.720 ;
        RECT 3.990 369.560 395.600 370.960 ;
        RECT 3.990 368.240 396.000 369.560 ;
        RECT 4.400 366.840 396.000 368.240 ;
        RECT 3.990 365.520 396.000 366.840 ;
        RECT 3.990 364.120 395.600 365.520 ;
        RECT 3.990 360.080 396.000 364.120 ;
        RECT 3.990 358.680 395.600 360.080 ;
        RECT 3.990 357.360 396.000 358.680 ;
        RECT 4.400 355.960 396.000 357.360 ;
        RECT 3.990 354.640 396.000 355.960 ;
        RECT 3.990 353.240 395.600 354.640 ;
        RECT 3.990 349.200 396.000 353.240 ;
        RECT 3.990 347.800 395.600 349.200 ;
        RECT 3.990 346.480 396.000 347.800 ;
        RECT 4.400 345.080 396.000 346.480 ;
        RECT 3.990 343.760 396.000 345.080 ;
        RECT 3.990 342.360 395.600 343.760 ;
        RECT 3.990 338.320 396.000 342.360 ;
        RECT 3.990 336.920 395.600 338.320 ;
        RECT 3.990 335.600 396.000 336.920 ;
        RECT 4.400 334.200 396.000 335.600 ;
        RECT 3.990 332.880 396.000 334.200 ;
        RECT 3.990 331.480 395.600 332.880 ;
        RECT 3.990 327.440 396.000 331.480 ;
        RECT 3.990 326.040 395.600 327.440 ;
        RECT 3.990 324.720 396.000 326.040 ;
        RECT 4.400 323.320 396.000 324.720 ;
        RECT 3.990 322.000 396.000 323.320 ;
        RECT 3.990 320.600 395.600 322.000 ;
        RECT 3.990 316.560 396.000 320.600 ;
        RECT 3.990 315.160 395.600 316.560 ;
        RECT 3.990 313.840 396.000 315.160 ;
        RECT 4.400 312.440 396.000 313.840 ;
        RECT 3.990 311.120 396.000 312.440 ;
        RECT 3.990 309.720 395.600 311.120 ;
        RECT 3.990 305.680 396.000 309.720 ;
        RECT 3.990 304.280 395.600 305.680 ;
        RECT 3.990 302.960 396.000 304.280 ;
        RECT 4.400 301.560 396.000 302.960 ;
        RECT 3.990 300.240 396.000 301.560 ;
        RECT 3.990 298.840 395.600 300.240 ;
        RECT 3.990 294.800 396.000 298.840 ;
        RECT 3.990 293.400 395.600 294.800 ;
        RECT 3.990 292.080 396.000 293.400 ;
        RECT 4.400 290.680 396.000 292.080 ;
        RECT 3.990 289.360 396.000 290.680 ;
        RECT 3.990 287.960 395.600 289.360 ;
        RECT 3.990 283.920 396.000 287.960 ;
        RECT 3.990 282.520 395.600 283.920 ;
        RECT 3.990 281.200 396.000 282.520 ;
        RECT 4.400 279.800 396.000 281.200 ;
        RECT 3.990 278.480 396.000 279.800 ;
        RECT 3.990 277.080 395.600 278.480 ;
        RECT 3.990 273.040 396.000 277.080 ;
        RECT 3.990 271.640 395.600 273.040 ;
        RECT 3.990 270.320 396.000 271.640 ;
        RECT 4.400 268.920 396.000 270.320 ;
        RECT 3.990 267.600 396.000 268.920 ;
        RECT 3.990 266.200 395.600 267.600 ;
        RECT 3.990 262.160 396.000 266.200 ;
        RECT 3.990 260.760 395.600 262.160 ;
        RECT 3.990 259.440 396.000 260.760 ;
        RECT 4.400 258.040 396.000 259.440 ;
        RECT 3.990 256.720 396.000 258.040 ;
        RECT 3.990 255.320 395.600 256.720 ;
        RECT 3.990 251.280 396.000 255.320 ;
        RECT 3.990 249.880 395.600 251.280 ;
        RECT 3.990 248.560 396.000 249.880 ;
        RECT 4.400 247.160 396.000 248.560 ;
        RECT 3.990 245.840 396.000 247.160 ;
        RECT 3.990 244.440 395.600 245.840 ;
        RECT 3.990 240.400 396.000 244.440 ;
        RECT 3.990 239.000 395.600 240.400 ;
        RECT 3.990 237.680 396.000 239.000 ;
        RECT 4.400 236.280 396.000 237.680 ;
        RECT 3.990 234.960 396.000 236.280 ;
        RECT 3.990 233.560 395.600 234.960 ;
        RECT 3.990 229.520 396.000 233.560 ;
        RECT 3.990 228.120 395.600 229.520 ;
        RECT 3.990 226.800 396.000 228.120 ;
        RECT 4.400 225.400 396.000 226.800 ;
        RECT 3.990 224.080 396.000 225.400 ;
        RECT 3.990 222.680 395.600 224.080 ;
        RECT 3.990 218.640 396.000 222.680 ;
        RECT 3.990 217.240 395.600 218.640 ;
        RECT 3.990 215.920 396.000 217.240 ;
        RECT 4.400 214.520 396.000 215.920 ;
        RECT 3.990 213.200 396.000 214.520 ;
        RECT 3.990 211.800 395.600 213.200 ;
        RECT 3.990 207.760 396.000 211.800 ;
        RECT 3.990 206.360 395.600 207.760 ;
        RECT 3.990 205.040 396.000 206.360 ;
        RECT 4.400 203.640 396.000 205.040 ;
        RECT 3.990 202.320 396.000 203.640 ;
        RECT 3.990 200.920 395.600 202.320 ;
        RECT 3.990 196.880 396.000 200.920 ;
        RECT 3.990 195.480 395.600 196.880 ;
        RECT 3.990 194.160 396.000 195.480 ;
        RECT 4.400 192.760 396.000 194.160 ;
        RECT 3.990 191.440 396.000 192.760 ;
        RECT 3.990 190.040 395.600 191.440 ;
        RECT 3.990 186.000 396.000 190.040 ;
        RECT 3.990 184.600 395.600 186.000 ;
        RECT 3.990 183.280 396.000 184.600 ;
        RECT 4.400 181.880 396.000 183.280 ;
        RECT 3.990 180.560 396.000 181.880 ;
        RECT 3.990 179.160 395.600 180.560 ;
        RECT 3.990 175.120 396.000 179.160 ;
        RECT 3.990 173.720 395.600 175.120 ;
        RECT 3.990 172.400 396.000 173.720 ;
        RECT 4.400 171.000 396.000 172.400 ;
        RECT 3.990 169.680 396.000 171.000 ;
        RECT 3.990 168.280 395.600 169.680 ;
        RECT 3.990 164.240 396.000 168.280 ;
        RECT 3.990 162.840 395.600 164.240 ;
        RECT 3.990 161.520 396.000 162.840 ;
        RECT 4.400 160.120 396.000 161.520 ;
        RECT 3.990 158.800 396.000 160.120 ;
        RECT 3.990 157.400 395.600 158.800 ;
        RECT 3.990 153.360 396.000 157.400 ;
        RECT 3.990 151.960 395.600 153.360 ;
        RECT 3.990 150.640 396.000 151.960 ;
        RECT 4.400 149.240 396.000 150.640 ;
        RECT 3.990 147.920 396.000 149.240 ;
        RECT 3.990 146.520 395.600 147.920 ;
        RECT 3.990 142.480 396.000 146.520 ;
        RECT 3.990 141.080 395.600 142.480 ;
        RECT 3.990 139.760 396.000 141.080 ;
        RECT 4.400 138.360 396.000 139.760 ;
        RECT 3.990 137.040 396.000 138.360 ;
        RECT 3.990 135.640 395.600 137.040 ;
        RECT 3.990 131.600 396.000 135.640 ;
        RECT 3.990 130.200 395.600 131.600 ;
        RECT 3.990 128.880 396.000 130.200 ;
        RECT 4.400 127.480 396.000 128.880 ;
        RECT 3.990 126.160 396.000 127.480 ;
        RECT 3.990 124.760 395.600 126.160 ;
        RECT 3.990 120.720 396.000 124.760 ;
        RECT 3.990 119.320 395.600 120.720 ;
        RECT 3.990 118.000 396.000 119.320 ;
        RECT 4.400 116.600 396.000 118.000 ;
        RECT 3.990 115.280 396.000 116.600 ;
        RECT 3.990 113.880 395.600 115.280 ;
        RECT 3.990 109.840 396.000 113.880 ;
        RECT 3.990 108.440 395.600 109.840 ;
        RECT 3.990 107.120 396.000 108.440 ;
        RECT 4.400 105.720 396.000 107.120 ;
        RECT 3.990 104.400 396.000 105.720 ;
        RECT 3.990 103.000 395.600 104.400 ;
        RECT 3.990 98.960 396.000 103.000 ;
        RECT 3.990 97.560 395.600 98.960 ;
        RECT 3.990 96.240 396.000 97.560 ;
        RECT 4.400 94.840 396.000 96.240 ;
        RECT 3.990 93.520 396.000 94.840 ;
        RECT 3.990 92.120 395.600 93.520 ;
        RECT 3.990 88.080 396.000 92.120 ;
        RECT 3.990 86.680 395.600 88.080 ;
        RECT 3.990 85.360 396.000 86.680 ;
        RECT 4.400 83.960 396.000 85.360 ;
        RECT 3.990 82.640 396.000 83.960 ;
        RECT 3.990 81.240 395.600 82.640 ;
        RECT 3.990 77.200 396.000 81.240 ;
        RECT 3.990 75.800 395.600 77.200 ;
        RECT 3.990 74.480 396.000 75.800 ;
        RECT 4.400 73.080 396.000 74.480 ;
        RECT 3.990 71.760 396.000 73.080 ;
        RECT 3.990 70.360 395.600 71.760 ;
        RECT 3.990 66.320 396.000 70.360 ;
        RECT 3.990 64.920 395.600 66.320 ;
        RECT 3.990 63.600 396.000 64.920 ;
        RECT 4.400 62.200 396.000 63.600 ;
        RECT 3.990 60.880 396.000 62.200 ;
        RECT 3.990 59.480 395.600 60.880 ;
        RECT 3.990 55.440 396.000 59.480 ;
        RECT 3.990 54.040 395.600 55.440 ;
        RECT 3.990 52.720 396.000 54.040 ;
        RECT 4.400 51.320 396.000 52.720 ;
        RECT 3.990 50.000 396.000 51.320 ;
        RECT 3.990 48.600 395.600 50.000 ;
        RECT 3.990 44.560 396.000 48.600 ;
        RECT 3.990 43.160 395.600 44.560 ;
        RECT 3.990 41.840 396.000 43.160 ;
        RECT 4.400 40.440 396.000 41.840 ;
        RECT 3.990 39.120 396.000 40.440 ;
        RECT 3.990 37.720 395.600 39.120 ;
        RECT 3.990 33.680 396.000 37.720 ;
        RECT 3.990 32.280 395.600 33.680 ;
        RECT 3.990 30.960 396.000 32.280 ;
        RECT 4.400 29.560 396.000 30.960 ;
        RECT 3.990 28.240 396.000 29.560 ;
        RECT 3.990 26.840 395.600 28.240 ;
        RECT 3.990 20.080 396.000 26.840 ;
        RECT 4.400 18.680 396.000 20.080 ;
        RECT 3.990 9.200 396.000 18.680 ;
        RECT 4.400 8.340 396.000 9.200 ;
      LAYER met4 ;
        RECT 16.855 10.240 17.620 386.745 ;
        RECT 20.020 10.240 54.320 386.745 ;
        RECT 56.720 10.240 57.620 386.745 ;
        RECT 60.020 10.240 94.320 386.745 ;
        RECT 96.720 10.240 97.620 386.745 ;
        RECT 100.020 10.240 134.320 386.745 ;
        RECT 136.720 10.240 137.620 386.745 ;
        RECT 140.020 10.240 174.320 386.745 ;
        RECT 176.720 10.240 177.620 386.745 ;
        RECT 180.020 10.240 214.320 386.745 ;
        RECT 216.720 10.240 217.620 386.745 ;
        RECT 220.020 10.240 254.320 386.745 ;
        RECT 256.720 10.240 257.620 386.745 ;
        RECT 260.020 10.240 294.320 386.745 ;
        RECT 296.720 10.240 297.620 386.745 ;
        RECT 300.020 10.240 334.320 386.745 ;
        RECT 336.720 10.240 337.620 386.745 ;
        RECT 340.020 10.240 358.505 386.745 ;
        RECT 16.855 8.335 358.505 10.240 ;
  END
END TopModule
END LIBRARY

